VERSION 5.8 ;
BUSBITCHARS "[]" ;
DIVIDERCHAR "/" ;
UNITS
    DATABASE MICRONS 1000 ;
END UNITS

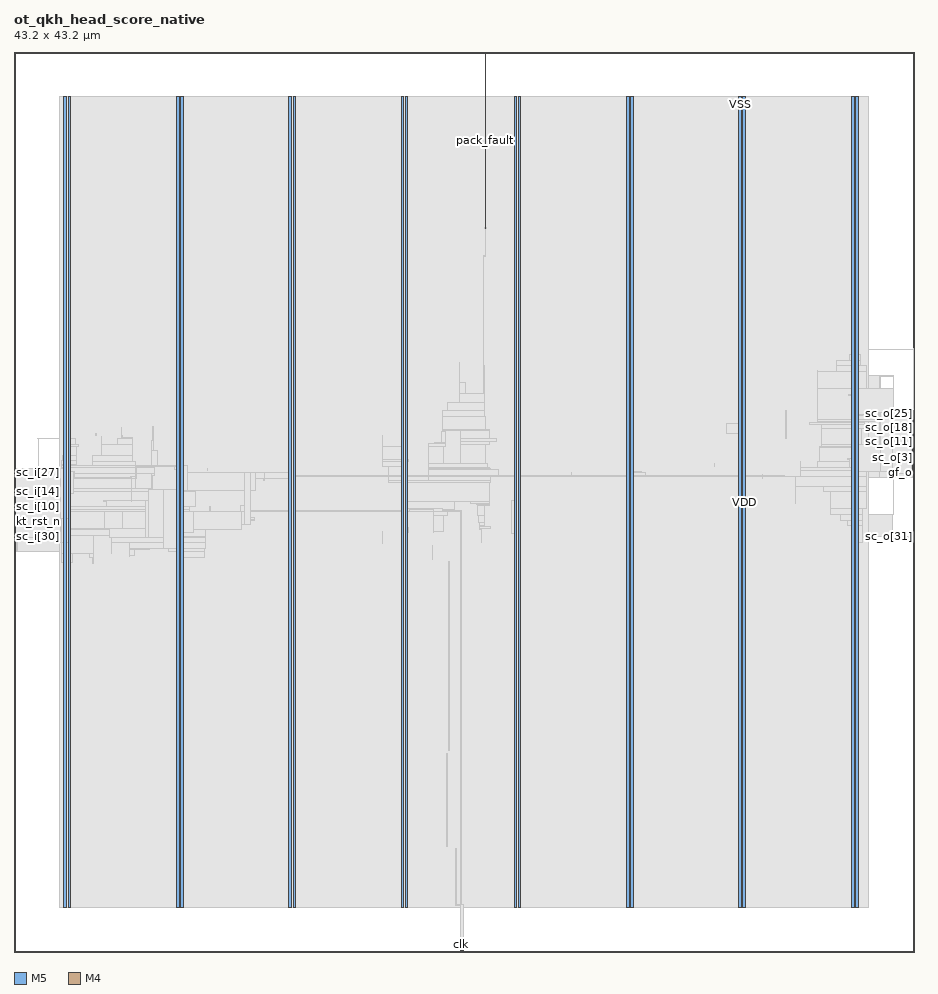
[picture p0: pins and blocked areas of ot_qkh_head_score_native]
MACRO ot_qkh_head_score_native
  FOREIGN ot_qkh_head_score_native 0 0 ;
  CLASS BLOCK ;
  SIZE 43.2 BY 43.2 ;
  PIN clk
    DIRECTION INPUT ;
    USE SIGNAL ;
    PORT
      LAYER M5 ;
        RECT  21.456 0 21.48 0.084 ;
    END
  END clk
  PIN gf_i
    DIRECTION INPUT ;
    USE SIGNAL ;
    PORT
      LAYER M4 ;
        RECT  0 20.208 0.084 20.232 ;
    END
  END gf_i
  PIN gf_o
    DIRECTION OUTPUT ;
    USE SIGNAL ;
    PORT
      LAYER M4 ;
        RECT  43.116 22.992 43.2 23.016 ;
    END
  END gf_o
  PIN kt_rst_n
    DIRECTION OUTPUT ;
    USE SIGNAL ;
    PORT
      LAYER M4 ;
        RECT  0 20.304 0.084 20.328 ;
    END
  END kt_rst_n
  PIN pack_fault
    DIRECTION INPUT ;
    USE SIGNAL ;
    PORT
      LAYER M5 ;
        RECT  22.608 43.116 22.632 43.2 ;
    END
    PORT
      LAYER M5 ;
        RECT  22.608 34.741 22.632 43.152 ;
    END
  END pack_fault
  PIN rst_n
    DIRECTION INPUT ;
    USE SIGNAL ;
    PORT
      LAYER M5 ;
        RECT  21.552 0 21.576 0.084 ;
    END
  END rst_n
  PIN sc_i[0]
    DIRECTION INPUT ;
    USE SIGNAL ;
    PORT
      LAYER M4 ;
        RECT  0 20.4 0.084 20.424 ;
    END
  END sc_i[0]
  PIN sc_i[10]
    DIRECTION INPUT ;
    USE SIGNAL ;
    PORT
      LAYER M4 ;
        RECT  0 21.36 0.084 21.384 ;
    END
  END sc_i[10]
  PIN sc_i[11]
    DIRECTION INPUT ;
    USE SIGNAL ;
    PORT
      LAYER M4 ;
        RECT  0 21.456 0.084 21.48 ;
    END
  END sc_i[11]
  PIN sc_i[12]
    DIRECTION INPUT ;
    USE SIGNAL ;
    PORT
      LAYER M4 ;
        RECT  0 21.552 0.084 21.576 ;
    END
  END sc_i[12]
  PIN sc_i[13]
    DIRECTION INPUT ;
    USE SIGNAL ;
    PORT
      LAYER M4 ;
        RECT  0 21.648 0.084 21.672 ;
    END
  END sc_i[13]
  PIN sc_i[14]
    DIRECTION INPUT ;
    USE SIGNAL ;
    PORT
      LAYER M4 ;
        RECT  0 21.744 0.084 21.768 ;
    END
  END sc_i[14]
  PIN sc_i[15]
    DIRECTION INPUT ;
    USE SIGNAL ;
    PORT
      LAYER M4 ;
        RECT  0 21.84 0.084 21.864 ;
    END
  END sc_i[15]
  PIN sc_i[16]
    DIRECTION INPUT ;
    USE SIGNAL ;
    PORT
      LAYER M4 ;
        RECT  0 21.936 0.084 21.96 ;
    END
  END sc_i[16]
  PIN sc_i[17]
    DIRECTION INPUT ;
    USE SIGNAL ;
    PORT
      LAYER M4 ;
        RECT  0 22.032 0.084 22.056 ;
    END
  END sc_i[17]
  PIN sc_i[18]
    DIRECTION INPUT ;
    USE SIGNAL ;
    PORT
      LAYER M4 ;
        RECT  0 22.128 0.084 22.152 ;
    END
  END sc_i[18]
  PIN sc_i[19]
    DIRECTION INPUT ;
    USE SIGNAL ;
    PORT
      LAYER M4 ;
        RECT  0 22.224 0.084 22.248 ;
    END
  END sc_i[19]
  PIN sc_i[1]
    DIRECTION INPUT ;
    USE SIGNAL ;
    PORT
      LAYER M4 ;
        RECT  0 20.496 0.084 20.52 ;
    END
  END sc_i[1]
  PIN sc_i[20]
    DIRECTION INPUT ;
    USE SIGNAL ;
    PORT
      LAYER M4 ;
        RECT  0 22.32 0.084 22.344 ;
    END
  END sc_i[20]
  PIN sc_i[21]
    DIRECTION INPUT ;
    USE SIGNAL ;
    PORT
      LAYER M4 ;
        RECT  0 22.416 0.084 22.44 ;
    END
  END sc_i[21]
  PIN sc_i[22]
    DIRECTION INPUT ;
    USE SIGNAL ;
    PORT
      LAYER M4 ;
        RECT  0 22.512 0.084 22.536 ;
    END
  END sc_i[22]
  PIN sc_i[23]
    DIRECTION INPUT ;
    USE SIGNAL ;
    PORT
      LAYER M4 ;
        RECT  0 22.608 0.084 22.632 ;
    END
  END sc_i[23]
  PIN sc_i[24]
    DIRECTION INPUT ;
    USE SIGNAL ;
    PORT
      LAYER M4 ;
        RECT  0 22.704 0.084 22.728 ;
    END
  END sc_i[24]
  PIN sc_i[25]
    DIRECTION INPUT ;
    USE SIGNAL ;
    PORT
      LAYER M4 ;
        RECT  0 22.8 0.084 22.824 ;
    END
  END sc_i[25]
  PIN sc_i[26]
    DIRECTION INPUT ;
    USE SIGNAL ;
    PORT
      LAYER M4 ;
        RECT  0 22.896 0.084 22.92 ;
    END
  END sc_i[26]
  PIN sc_i[27]
    DIRECTION INPUT ;
    USE SIGNAL ;
    PORT
      LAYER M4 ;
        RECT  0 22.992 0.084 23.016 ;
    END
  END sc_i[27]
  PIN sc_i[28]
    DIRECTION INPUT ;
    USE SIGNAL ;
    PORT
      LAYER M4 ;
        RECT  0 23.088 0.084 23.112 ;
    END
  END sc_i[28]
  PIN sc_i[29]
    DIRECTION INPUT ;
    USE SIGNAL ;
    PORT
      LAYER M4 ;
        RECT  0 23.184 0.084 23.208 ;
    END
  END sc_i[29]
  PIN sc_i[2]
    DIRECTION INPUT ;
    USE SIGNAL ;
    PORT
      LAYER M4 ;
        RECT  0 20.592 0.084 20.616 ;
    END
  END sc_i[2]
  PIN sc_i[30]
    DIRECTION INPUT ;
    USE SIGNAL ;
    PORT
      LAYER M4 ;
        RECT  0 19.92 0.084 19.944 ;
    END
  END sc_i[30]
  PIN sc_i[31]
    DIRECTION INPUT ;
    USE SIGNAL ;
    PORT
      LAYER M4 ;
        RECT  0 20.016 0.084 20.04 ;
    END
  END sc_i[31]
  PIN sc_i[3]
    DIRECTION INPUT ;
    USE SIGNAL ;
    PORT
      LAYER M4 ;
        RECT  0 20.688 0.084 20.712 ;
    END
  END sc_i[3]
  PIN sc_i[4]
    DIRECTION INPUT ;
    USE SIGNAL ;
    PORT
      LAYER M4 ;
        RECT  0 20.784 0.084 20.808 ;
    END
  END sc_i[4]
  PIN sc_i[5]
    DIRECTION INPUT ;
    USE SIGNAL ;
    PORT
      LAYER M4 ;
        RECT  0 20.88 0.084 20.904 ;
    END
  END sc_i[5]
  PIN sc_i[6]
    DIRECTION INPUT ;
    USE SIGNAL ;
    PORT
      LAYER M4 ;
        RECT  0 20.976 0.084 21 ;
    END
  END sc_i[6]
  PIN sc_i[7]
    DIRECTION INPUT ;
    USE SIGNAL ;
    PORT
      LAYER M4 ;
        RECT  0 21.072 0.084 21.096 ;
    END
  END sc_i[7]
  PIN sc_i[8]
    DIRECTION INPUT ;
    USE SIGNAL ;
    PORT
      LAYER M4 ;
        RECT  0 21.168 0.084 21.192 ;
    END
  END sc_i[8]
  PIN sc_i[9]
    DIRECTION INPUT ;
    USE SIGNAL ;
    PORT
      LAYER M4 ;
        RECT  0 21.264 0.084 21.288 ;
    END
  END sc_i[9]
  PIN sc_o[0]
    DIRECTION OUTPUT ;
    USE SIGNAL ;
    PORT
      LAYER M4 ;
        RECT  43.116 23.088 43.2 23.112 ;
    END
  END sc_o[0]
  PIN sc_o[10]
    DIRECTION OUTPUT ;
    USE SIGNAL ;
    PORT
      LAYER M4 ;
        RECT  43.116 24.048 43.2 24.072 ;
    END
  END sc_o[10]
  PIN sc_o[11]
    DIRECTION OUTPUT ;
    USE SIGNAL ;
    PORT
      LAYER M4 ;
        RECT  43.116 24.144 43.2 24.168 ;
    END
  END sc_o[11]
  PIN sc_o[12]
    DIRECTION OUTPUT ;
    USE SIGNAL ;
    PORT
      LAYER M4 ;
        RECT  43.116 24.24 43.2 24.264 ;
    END
  END sc_o[12]
  PIN sc_o[13]
    DIRECTION OUTPUT ;
    USE SIGNAL ;
    PORT
      LAYER M4 ;
        RECT  43.116 24.336 43.2 24.36 ;
    END
  END sc_o[13]
  PIN sc_o[14]
    DIRECTION OUTPUT ;
    USE SIGNAL ;
    PORT
      LAYER M4 ;
        RECT  43.116 24.432 43.2 24.456 ;
    END
  END sc_o[14]
  PIN sc_o[15]
    DIRECTION OUTPUT ;
    USE SIGNAL ;
    PORT
      LAYER M4 ;
        RECT  43.116 24.528 43.2 24.552 ;
    END
  END sc_o[15]
  PIN sc_o[16]
    DIRECTION OUTPUT ;
    USE SIGNAL ;
    PORT
      LAYER M4 ;
        RECT  43.116 24.624 43.2 24.648 ;
    END
  END sc_o[16]
  PIN sc_o[17]
    DIRECTION OUTPUT ;
    USE SIGNAL ;
    PORT
      LAYER M4 ;
        RECT  43.116 24.72 43.2 24.744 ;
    END
  END sc_o[17]
  PIN sc_o[18]
    DIRECTION OUTPUT ;
    USE SIGNAL ;
    PORT
      LAYER M4 ;
        RECT  43.116 24.816 43.2 24.84 ;
    END
  END sc_o[18]
  PIN sc_o[19]
    DIRECTION OUTPUT ;
    USE SIGNAL ;
    PORT
      LAYER M4 ;
        RECT  43.116 24.912 43.2 24.936 ;
    END
  END sc_o[19]
  PIN sc_o[1]
    DIRECTION OUTPUT ;
    USE SIGNAL ;
    PORT
      LAYER M4 ;
        RECT  43.116 23.184 43.2 23.208 ;
    END
  END sc_o[1]
  PIN sc_o[20]
    DIRECTION OUTPUT ;
    USE SIGNAL ;
    PORT
      LAYER M4 ;
        RECT  43.116 25.008 43.2 25.032 ;
    END
  END sc_o[20]
  PIN sc_o[21]
    DIRECTION OUTPUT ;
    USE SIGNAL ;
    PORT
      LAYER M4 ;
        RECT  43.116 25.104 43.2 25.128 ;
    END
  END sc_o[21]
  PIN sc_o[22]
    DIRECTION OUTPUT ;
    USE SIGNAL ;
    PORT
      LAYER M4 ;
        RECT  43.116 25.2 43.2 25.224 ;
    END
  END sc_o[22]
  PIN sc_o[23]
    DIRECTION OUTPUT ;
    USE SIGNAL ;
    PORT
      LAYER M4 ;
        RECT  43.116 25.296 43.2 25.32 ;
    END
  END sc_o[23]
  PIN sc_o[24]
    DIRECTION OUTPUT ;
    USE SIGNAL ;
    PORT
      LAYER M4 ;
        RECT  43.116 25.392 43.2 25.416 ;
    END
  END sc_o[24]
  PIN sc_o[25]
    DIRECTION OUTPUT ;
    USE SIGNAL ;
    PORT
      LAYER M4 ;
        RECT  43.116 25.488 43.2 25.512 ;
    END
  END sc_o[25]
  PIN sc_o[26]
    DIRECTION OUTPUT ;
    USE SIGNAL ;
    PORT
      LAYER M4 ;
        RECT  43.116 25.584 43.2 25.608 ;
    END
  END sc_o[26]
  PIN sc_o[27]
    DIRECTION OUTPUT ;
    USE SIGNAL ;
    PORT
      LAYER M4 ;
        RECT  43.116 25.68 43.2 25.704 ;
    END
  END sc_o[27]
  PIN sc_o[28]
    DIRECTION OUTPUT ;
    USE SIGNAL ;
    PORT
      LAYER M4 ;
        RECT  43.116 25.776 43.2 25.8 ;
    END
  END sc_o[28]
  PIN sc_o[29]
    DIRECTION OUTPUT ;
    USE SIGNAL ;
    PORT
      LAYER M4 ;
        RECT  43.116 25.872 43.2 25.896 ;
    END
  END sc_o[29]
  PIN sc_o[2]
    DIRECTION OUTPUT ;
    USE SIGNAL ;
    PORT
      LAYER M4 ;
        RECT  43.116 23.28 43.2 23.304 ;
    END
  END sc_o[2]
  PIN sc_o[30]
    DIRECTION OUTPUT ;
    USE SIGNAL ;
    PORT
      LAYER M4 ;
        RECT  43.116 25.968 43.2 25.992 ;
    END
  END sc_o[30]
  PIN sc_o[31]
    DIRECTION OUTPUT ;
    USE SIGNAL ;
    PORT
      LAYER M4 ;
        RECT  43.116 19.92 43.2 19.944 ;
    END
  END sc_o[31]
  PIN sc_o[3]
    DIRECTION OUTPUT ;
    USE SIGNAL ;
    PORT
      LAYER M4 ;
        RECT  43.116 23.376 43.2 23.4 ;
    END
  END sc_o[3]
  PIN sc_o[4]
    DIRECTION OUTPUT ;
    USE SIGNAL ;
    PORT
      LAYER M4 ;
        RECT  43.116 23.472 43.2 23.496 ;
    END
  END sc_o[4]
  PIN sc_o[5]
    DIRECTION OUTPUT ;
    USE SIGNAL ;
    PORT
      LAYER M4 ;
        RECT  43.116 23.568 43.2 23.592 ;
    END
  END sc_o[5]
  PIN sc_o[6]
    DIRECTION OUTPUT ;
    USE SIGNAL ;
    PORT
      LAYER M4 ;
        RECT  43.116 23.664 43.2 23.688 ;
    END
  END sc_o[6]
  PIN sc_o[7]
    DIRECTION OUTPUT ;
    USE SIGNAL ;
    PORT
      LAYER M4 ;
        RECT  43.116 23.76 43.2 23.784 ;
    END
  END sc_o[7]
  PIN sc_o[8]
    DIRECTION OUTPUT ;
    USE SIGNAL ;
    PORT
      LAYER M4 ;
        RECT  43.116 23.856 43.2 23.88 ;
    END
  END sc_o[8]
  PIN sc_o[9]
    DIRECTION OUTPUT ;
    USE SIGNAL ;
    PORT
      LAYER M4 ;
        RECT  43.116 23.952 43.2 23.976 ;
    END
  END sc_o[9]
  PIN sf_i
    DIRECTION INPUT ;
    USE SIGNAL ;
    PORT
      LAYER M4 ;
        RECT  0 20.112 0.084 20.136 ;
    END
  END sf_i
  PIN sf_o
    DIRECTION OUTPUT ;
    USE SIGNAL ;
    PORT
      LAYER M4 ;
        RECT  43.116 20.016 43.2 20.04 ;
    END
  END sf_o
  PIN VDD
    DIRECTION INOUT ;
    USE POWER ;
    PORT
      LAYER M5 ;
        RECT  40.392 2.151 40.512 41.049 ;
        RECT  34.992 2.151 35.112 41.049 ;
        RECT  29.592 2.151 29.712 41.049 ;
        RECT  24.192 2.151 24.312 41.049 ;
        RECT  18.792 2.151 18.912 41.049 ;
        RECT  13.392 2.151 13.512 41.049 ;
        RECT  7.992 2.151 8.112 41.049 ;
        RECT  2.592 2.151 2.712 41.049 ;
    END
  END VDD
  PIN VSS
    DIRECTION INOUT ;
    USE GROUND ;
    PORT
      LAYER M5 ;
        RECT  40.2 2.137 40.32 41.063 ;
        RECT  34.8 2.137 34.92 41.063 ;
        RECT  29.4 2.137 29.52 41.063 ;
        RECT  24 2.137 24.12 41.063 ;
        RECT  18.6 2.137 18.72 41.063 ;
        RECT  13.2 2.137 13.32 41.063 ;
        RECT  7.8 2.137 7.92 41.063 ;
        RECT  2.4 2.137 2.52 41.063 ;
    END
  END VSS
  # OT_OBS_CLOSED layer=M5 d_um=1.536 added=1
  OBS
    LAYER RVTN ;
     RECT  2.16 2.16 41.04 2.295 ;
     RECT  2.16 2.565 41.04 2.835 ;
     RECT  2.16 3.105 41.04 3.375 ;
     RECT  2.16 3.645 41.04 3.915 ;
     RECT  2.16 4.185 41.04 4.455 ;
     RECT  2.16 4.725 41.04 4.995 ;
     RECT  2.16 5.265 41.04 5.535 ;
     RECT  2.16 5.805 41.04 6.075 ;
     RECT  2.16 6.345 41.04 6.615 ;
     RECT  2.16 6.885 41.04 7.155 ;
     RECT  2.16 7.425 41.04 7.695 ;
     RECT  2.16 7.965 41.04 8.235 ;
     RECT  2.16 8.505 41.04 8.775 ;
     RECT  2.16 9.045 41.04 9.315 ;
     RECT  2.16 9.585 41.04 9.855 ;
     RECT  2.16 10.125 41.04 10.395 ;
     RECT  2.16 10.665 41.04 10.935 ;
     RECT  2.16 11.205 41.04 11.475 ;
     RECT  2.16 11.745 41.04 12.015 ;
     RECT  2.16 12.285 41.04 12.555 ;
     RECT  2.16 12.825 41.04 13.095 ;
     RECT  2.16 13.365 41.04 13.635 ;
     RECT  2.16 13.905 41.04 14.175 ;
     RECT  2.16 14.445 41.04 14.715 ;
     RECT  2.16 14.985 41.04 15.255 ;
     RECT  2.16 15.525 41.04 15.795 ;
     RECT  2.16 16.065 41.04 16.335 ;
     RECT  2.16 16.605 41.04 16.875 ;
     RECT  2.16 17.145 41.04 17.415 ;
     RECT  2.16 17.685 41.04 17.955 ;
     RECT  2.16 18.225 41.04 18.495 ;
     RECT  2.16 18.765 41.04 19.035 ;
     RECT  2.16 19.305 41.04 19.575 ;
     RECT  2.16 19.845 41.04 20.115 ;
     RECT  2.16 20.385 41.04 20.655 ;
     RECT  2.16 20.925 41.04 21.195 ;
     RECT  2.16 21.465 41.04 21.735 ;
     RECT  2.16 22.005 41.04 22.275 ;
     RECT  2.16 22.545 41.04 22.815 ;
     RECT  2.16 23.085 41.04 23.355 ;
     RECT  2.16 23.625 41.04 23.895 ;
     RECT  2.16 24.165 41.04 24.435 ;
     RECT  2.16 24.705 41.04 24.975 ;
     RECT  2.16 25.245 41.04 25.515 ;
     RECT  2.16 25.785 41.04 26.055 ;
     RECT  2.16 26.325 41.04 26.595 ;
     RECT  2.16 26.865 41.04 27.135 ;
     RECT  2.16 27.405 41.04 27.675 ;
     RECT  2.16 27.945 41.04 28.215 ;
     RECT  2.16 28.485 41.04 28.755 ;
     RECT  2.16 29.025 41.04 29.295 ;
     RECT  2.16 29.565 41.04 29.835 ;
     RECT  2.16 30.105 41.04 30.375 ;
     RECT  2.16 30.645 41.04 30.915 ;
     RECT  2.16 31.185 41.04 31.455 ;
     RECT  2.16 31.725 41.04 31.995 ;
     RECT  2.16 32.265 41.04 32.535 ;
     RECT  2.16 32.805 41.04 33.075 ;
     RECT  2.16 33.345 41.04 33.615 ;
     RECT  2.16 33.885 41.04 34.155 ;
     RECT  2.16 34.425 41.04 34.695 ;
     RECT  2.16 34.965 41.04 35.235 ;
     RECT  2.16 35.505 41.04 35.775 ;
     RECT  2.16 36.045 41.04 36.315 ;
     RECT  2.16 36.585 41.04 36.855 ;
     RECT  2.16 37.125 41.04 37.395 ;
     RECT  2.16 37.665 41.04 37.935 ;
     RECT  2.16 38.205 41.04 38.475 ;
     RECT  2.16 38.745 41.04 39.015 ;
     RECT  2.16 39.285 41.04 39.555 ;
     RECT  2.16 39.825 41.04 40.095 ;
     RECT  2.16 40.365 41.04 40.635 ;
     RECT  2.16 40.905 41.04 41.04 ;
    LAYER RVTP ;
     RECT  2.16 2.295 41.04 2.565 ;
     RECT  2.16 2.835 41.04 3.105 ;
     RECT  2.16 3.375 41.04 3.645 ;
     RECT  2.16 3.915 41.04 4.185 ;
     RECT  2.16 4.455 41.04 4.725 ;
     RECT  2.16 4.995 41.04 5.265 ;
     RECT  2.16 5.535 41.04 5.805 ;
     RECT  2.16 6.075 41.04 6.345 ;
     RECT  2.16 6.615 41.04 6.885 ;
     RECT  2.16 7.155 41.04 7.425 ;
     RECT  2.16 7.695 41.04 7.965 ;
     RECT  2.16 8.235 41.04 8.505 ;
     RECT  2.16 8.775 41.04 9.045 ;
     RECT  2.16 9.315 41.04 9.585 ;
     RECT  2.16 9.855 41.04 10.125 ;
     RECT  2.16 10.395 41.04 10.665 ;
     RECT  2.16 10.935 41.04 11.205 ;
     RECT  2.16 11.475 41.04 11.745 ;
     RECT  2.16 12.015 41.04 12.285 ;
     RECT  2.16 12.555 41.04 12.825 ;
     RECT  2.16 13.095 41.04 13.365 ;
     RECT  2.16 13.635 41.04 13.905 ;
     RECT  2.16 14.175 41.04 14.445 ;
     RECT  2.16 14.715 41.04 14.985 ;
     RECT  2.16 15.255 41.04 15.525 ;
     RECT  2.16 15.795 41.04 16.065 ;
     RECT  2.16 16.335 41.04 16.605 ;
     RECT  2.16 16.875 41.04 17.145 ;
     RECT  2.16 17.415 41.04 17.685 ;
     RECT  2.16 17.955 41.04 18.225 ;
     RECT  2.16 18.495 41.04 18.765 ;
     RECT  2.16 19.035 41.04 19.305 ;
     RECT  2.16 19.575 41.04 19.845 ;
     RECT  2.16 20.115 41.04 20.385 ;
     RECT  2.16 20.655 41.04 20.925 ;
     RECT  2.16 21.195 41.04 21.465 ;
     RECT  2.16 21.735 41.04 22.005 ;
     RECT  2.16 22.275 41.04 22.545 ;
     RECT  2.16 22.815 41.04 23.085 ;
     RECT  2.16 23.355 41.04 23.625 ;
     RECT  2.16 23.895 41.04 24.165 ;
     RECT  2.16 24.435 41.04 24.705 ;
     RECT  2.16 24.975 41.04 25.245 ;
     RECT  2.16 25.515 41.04 25.785 ;
     RECT  2.16 26.055 41.04 26.325 ;
     RECT  2.16 26.595 41.04 26.865 ;
     RECT  2.16 27.135 41.04 27.405 ;
     RECT  2.16 27.675 41.04 27.945 ;
     RECT  2.16 28.215 41.04 28.485 ;
     RECT  2.16 28.755 41.04 29.025 ;
     RECT  2.16 29.295 41.04 29.565 ;
     RECT  2.16 29.835 41.04 30.105 ;
     RECT  2.16 30.375 41.04 30.645 ;
     RECT  2.16 30.915 41.04 31.185 ;
     RECT  2.16 31.455 41.04 31.725 ;
     RECT  2.16 31.995 41.04 32.265 ;
     RECT  2.16 32.535 41.04 32.805 ;
     RECT  2.16 33.075 41.04 33.345 ;
     RECT  2.16 33.615 41.04 33.885 ;
     RECT  2.16 34.155 41.04 34.425 ;
     RECT  2.16 34.695 41.04 34.965 ;
     RECT  2.16 35.235 41.04 35.505 ;
     RECT  2.16 35.775 41.04 36.045 ;
     RECT  2.16 36.315 41.04 36.585 ;
     RECT  2.16 36.855 41.04 37.125 ;
     RECT  2.16 37.395 41.04 37.665 ;
     RECT  2.16 37.935 41.04 38.205 ;
     RECT  2.16 38.475 41.04 38.745 ;
     RECT  2.16 39.015 41.04 39.285 ;
     RECT  2.16 39.555 41.04 39.825 ;
     RECT  2.16 40.095 41.04 40.365 ;
     RECT  2.16 40.635 41.04 40.905 ;
    LAYER M1 ;
     RECT  2.16 2.151 41.04 41.049 ;
    LAYER M2 ;
     RECT  0.103 19.656 0.139 19.674 ;
     RECT  0.139 19.242 0.175 19.674 ;
     RECT  0.175 19.242 2.16 19.908 ;
     RECT  0.175 20.7 2.16 20.718 ;
     RECT  0.535 22.014 2.16 22.032 ;
     RECT  1.147 24.642 2.16 24.66 ;
     RECT  2.16 2.151 41.04 41.049 ;
     RECT  41.04 22.788 41.567 27.666 ;
     RECT  41.567 26.568 41.603 27.666 ;
     RECT  41.603 26.568 41.891 26.586 ;
     RECT  41.04 19.926 42.179 21.024 ;
     RECT  41.567 22.788 42.179 25.704 ;
     RECT  42.179 21.006 42.215 21.024 ;
     RECT  41.603 27.648 42.215 27.666 ;
     RECT  42.179 19.926 43.115 19.944 ;
     RECT  42.179 22.788 43.115 23.922 ;
     RECT  41.04 28.926 43.187 28.944 ;
    LAYER M3 ;
     RECT  2.415 2.143 2.505 2.413 ;
     RECT  7.815 2.143 7.905 2.413 ;
     RECT  13.215 2.143 13.305 2.413 ;
     RECT  18.615 2.143 18.705 2.413 ;
     RECT  24.015 2.143 24.105 2.413 ;
     RECT  29.415 2.143 29.505 2.413 ;
     RECT  34.815 2.143 34.905 2.413 ;
     RECT  40.215 2.143 40.305 2.413 ;
     RECT  21.204 2.251 21.222 4.955 ;
     RECT  20.772 5.071 20.79 9.545 ;
     RECT  2.415 2.413 2.697 18.697 ;
     RECT  20.88 9.661 20.898 18.725 ;
     RECT  3.78 18.661 3.798 18.931 ;
     RECT  7.815 2.413 8.097 18.931 ;
     RECT  5.544 19.003 5.562 19.039 ;
     RECT  2.304 18.697 2.826 19.111 ;
     RECT  3.6 18.931 3.798 19.111 ;
     RECT  7.815 18.931 9.126 19.237 ;
     RECT  5.544 19.039 5.778 19.309 ;
     RECT  7.416 19.237 9.126 19.381 ;
     RECT  5.544 19.309 6.498 19.387 ;
     RECT  7.416 19.381 9.198 19.387 ;
     RECT  20.088 18.841 20.106 19.535 ;
     RECT  40.215 2.413 40.497 19.615 ;
     RECT  0.144 19.237 0.162 19.651 ;
     RECT  4.68 19.111 4.698 19.651 ;
     RECT  5.544 19.387 9.198 19.651 ;
     RECT  40.176 19.615 40.497 19.651 ;
     RECT  0.108 19.651 0.162 19.885 ;
     RECT  4.68 19.651 9.198 19.898 ;
     RECT  4.572 19.898 9.198 19.949 ;
     RECT  2.304 19.111 3.798 20.011 ;
     RECT  4.572 19.949 6.498 20.011 ;
     RECT  43.092 19.921 43.11 20.045 ;
     RECT  24.015 2.413 24.297 20.083 ;
     RECT  18.615 2.413 18.897 20.155 ;
     RECT  17.676 19.615 17.694 20.183 ;
     RECT  20.124 20.119 20.142 20.191 ;
     RECT  0.108 19.885 0.198 20.203 ;
     RECT  22.428 19.651 22.446 20.281 ;
     RECT  2.304 20.011 6.498 20.309 ;
     RECT  22.356 20.281 22.446 20.317 ;
     RECT  0.108 20.203 0.342 20.333 ;
     RECT  2.304 20.309 6.426 20.345 ;
     RECT  7.236 19.949 9.198 20.345 ;
     RECT  18.615 20.155 18.954 20.381 ;
     RECT  7.344 20.345 9.198 20.389 ;
     RECT  22.356 20.317 22.878 20.417 ;
     RECT  22.356 20.417 22.59 20.461 ;
     RECT  40.176 19.651 40.734 20.461 ;
     RECT  10.872 20.299 10.89 20.539 ;
     RECT  7.344 20.389 9.63 20.579 ;
     RECT  42.156 19.915 42.174 20.579 ;
     RECT  7.344 20.579 9.558 20.615 ;
     RECT  10.872 20.539 11.322 20.623 ;
     RECT  22.32 20.461 22.59 20.623 ;
     RECT  7.344 20.615 8.622 20.651 ;
     RECT  39.996 20.461 40.734 20.695 ;
     RECT  10.8 20.623 11.322 20.731 ;
     RECT  10.8 20.731 11.538 20.759 ;
     RECT  10.872 20.759 11.538 20.849 ;
     RECT  22.284 20.623 22.59 20.929 ;
     RECT  20.124 20.191 20.61 20.965 ;
     RECT  39.672 20.695 40.734 21.001 ;
     RECT  2.304 20.345 4.338 21.163 ;
     RECT  5.22 20.345 6.426 21.163 ;
     RECT  18.615 20.381 18.897 21.163 ;
     RECT  20.124 20.965 20.826 21.163 ;
     RECT  2.304 21.163 6.426 21.235 ;
     RECT  7.344 20.651 8.442 21.235 ;
     RECT  18.615 21.163 20.826 21.235 ;
     RECT  39.204 21.001 40.734 21.271 ;
     RECT  9.396 20.615 9.414 21.389 ;
     RECT  2.304 21.235 8.442 21.397 ;
     RECT  10.872 20.849 11.358 21.425 ;
     RECT  22.248 20.929 22.59 21.433 ;
     RECT  11.052 21.425 11.358 21.461 ;
     RECT  22.248 21.433 22.842 21.469 ;
     RECT  34.815 2.413 35.097 21.505 ;
     RECT  22.212 21.469 22.842 21.541 ;
     RECT  18.615 21.235 21.15 21.631 ;
     RECT  21.924 21.541 22.842 21.631 ;
     RECT  0.18 20.333 0.198 21.643 ;
     RECT  23.868 20.083 24.297 21.659 ;
     RECT  34.776 21.505 35.097 21.659 ;
     RECT  0.18 21.643 0.342 21.739 ;
     RECT  0.144 21.739 0.342 22.009 ;
     RECT  39.204 21.271 40.914 22.081 ;
     RECT  2.304 21.397 8.694 22.109 ;
     RECT  2.304 22.109 6.642 22.123 ;
     RECT  11.16 21.461 11.358 22.165 ;
     RECT  7.416 22.109 8.694 22.199 ;
     RECT  7.56 22.199 8.694 22.222 ;
     RECT  2.268 22.123 6.642 22.235 ;
     RECT  11.16 22.165 11.574 22.235 ;
     RECT  0.144 22.009 0.558 22.253 ;
     RECT  7.815 22.222 8.694 22.315 ;
     RECT  37.512 21.541 37.53 22.351 ;
     RECT  38.844 22.081 40.914 22.351 ;
     RECT  7.815 22.315 9.054 22.469 ;
     RECT  11.376 22.235 11.574 22.469 ;
     RECT  11.448 22.469 11.574 22.505 ;
     RECT  18.615 21.631 22.842 22.549 ;
     RECT  9.072 22.549 9.09 22.649 ;
     RECT  17.964 22.549 22.878 22.649 ;
     RECT  11.988 22.621 12.006 22.781 ;
     RECT  37.512 22.351 40.914 22.843 ;
     RECT  36.972 22.843 40.914 22.847 ;
     RECT  36.972 22.847 36.99 22.883 ;
     RECT  6.624 22.235 6.642 22.891 ;
     RECT  19.908 22.649 22.878 22.891 ;
     RECT  29.415 2.413 29.697 22.891 ;
     RECT  35.928 22.711 35.946 22.919 ;
     RECT  2.268 22.235 5.85 22.981 ;
     RECT  6.624 22.891 6.75 22.981 ;
     RECT  26.748 22.891 26.766 23.009 ;
     RECT  29.415 22.891 30.33 23.009 ;
     RECT  42.192 21.001 42.21 23.021 ;
     RECT  29.415 23.009 30.114 23.045 ;
     RECT  0.144 22.253 0.162 23.069 ;
     RECT  7.815 22.469 8.334 23.089 ;
     RECT  37.728 22.847 40.914 23.117 ;
     RECT  19.908 22.891 23.274 23.153 ;
     RECT  7.776 23.089 8.334 23.161 ;
     RECT  43.092 22.783 43.11 23.161 ;
     RECT  9.288 23.089 9.306 23.189 ;
     RECT  19.908 23.153 22.878 23.189 ;
     RECT  43.056 23.161 43.11 23.251 ;
     RECT  2.268 22.981 6.75 23.279 ;
     RECT  19.908 23.189 22.842 23.279 ;
     RECT  37.728 23.117 40.806 23.279 ;
     RECT  17.964 22.649 18.897 23.287 ;
     RECT  6.624 23.279 6.75 23.323 ;
     RECT  2.268 23.279 5.85 23.351 ;
     RECT  7.704 23.161 8.334 23.351 ;
     RECT  7.815 23.351 8.334 23.357 ;
     RECT  2.268 23.351 3.006 23.387 ;
     RECT  19.908 23.279 22.734 23.459 ;
     RECT  33.624 23.323 33.642 23.459 ;
     RECT  17.676 23.287 18.897 23.521 ;
     RECT  3.78 23.351 5.85 23.549 ;
     RECT  37.728 23.279 37.746 23.549 ;
     RECT  38.592 23.279 40.806 23.549 ;
     RECT  34.815 21.659 35.097 23.557 ;
     RECT  2.304 23.387 3.006 23.585 ;
     RECT  17.676 23.521 18.954 23.621 ;
     RECT  42.156 23.701 42.174 23.789 ;
     RECT  3.78 23.549 5.706 23.819 ;
     RECT  34.776 23.557 35.097 23.819 ;
     RECT  2.34 23.585 3.006 23.855 ;
     RECT  43.02 23.251 43.11 23.885 ;
     RECT  43.092 23.885 43.11 23.981 ;
     RECT  6.624 23.323 6.894 24.089 ;
     RECT  41.58 24.043 41.634 24.139 ;
     RECT  38.664 23.549 40.806 24.205 ;
     RECT  41.544 24.139 41.634 24.205 ;
     RECT  2.376 23.855 3.006 24.241 ;
     RECT  19.908 23.459 20.61 24.241 ;
     RECT  17.676 23.621 18.897 24.269 ;
     RECT  38.664 24.205 41.634 24.269 ;
     RECT  2.376 24.241 3.114 24.359 ;
     RECT  4.176 23.819 5.706 24.359 ;
     RECT  38.772 24.269 41.634 24.365 ;
     RECT  21.456 23.459 22.626 24.367 ;
     RECT  19.908 24.241 20.718 24.431 ;
     RECT  41.544 24.365 41.634 24.431 ;
     RECT  20.196 24.431 20.718 24.467 ;
     RECT  21.456 24.367 22.842 24.511 ;
     RECT  41.58 24.431 41.634 24.523 ;
     RECT  6.624 24.089 6.678 24.539 ;
     RECT  2.376 24.359 2.97 24.629 ;
     RECT  4.968 24.359 5.706 24.629 ;
     RECT  21.456 24.511 23.166 24.629 ;
     RECT  1.152 22.507 1.17 24.665 ;
     RECT  5.148 24.629 5.706 24.701 ;
     RECT  4.176 24.359 4.194 24.737 ;
     RECT  17.676 24.269 17.694 24.773 ;
     RECT  5.148 24.701 5.202 24.809 ;
     RECT  3.924 24.781 3.942 24.899 ;
     RECT  34.815 23.819 35.097 24.907 ;
     RECT  2.376 24.629 2.697 24.935 ;
     RECT  20.52 24.467 20.718 24.971 ;
     RECT  20.556 24.971 20.718 25.007 ;
     RECT  20.592 25.007 20.718 25.051 ;
     RECT  21.456 24.629 22.842 25.051 ;
     RECT  20.592 25.051 22.842 25.079 ;
     RECT  38.772 24.365 40.662 25.141 ;
     RECT  5.148 24.809 5.166 25.169 ;
     RECT  6.66 24.539 6.678 25.205 ;
     RECT  38.772 25.141 40.842 25.321 ;
     RECT  34.2 24.907 35.097 25.349 ;
     RECT  38.196 25.321 40.842 25.439 ;
     RECT  38.556 25.439 40.842 25.483 ;
     RECT  41.58 24.523 42.174 25.483 ;
     RECT  38.556 25.483 42.174 25.579 ;
     RECT  20.592 25.079 22.626 25.709 ;
     RECT  20.592 25.709 22.59 25.979 ;
     RECT  37.044 24.637 37.062 25.979 ;
     RECT  43.092 25.963 43.11 26.059 ;
     RECT  43.092 26.059 43.182 26.093 ;
     RECT  34.815 25.349 35.097 26.365 ;
     RECT  20.808 25.979 22.59 26.393 ;
     RECT  21.384 26.393 22.59 26.789 ;
     RECT  34.776 26.365 35.097 26.789 ;
     RECT  38.556 25.579 42.21 27.059 ;
     RECT  21.384 26.789 21.69 27.329 ;
     RECT  42.192 27.059 42.21 27.671 ;
     RECT  38.556 27.059 40.914 27.869 ;
     RECT  38.556 27.869 38.574 27.905 ;
     RECT  22.536 26.789 22.59 28.139 ;
     RECT  39.456 27.869 40.914 28.139 ;
     RECT  39.456 28.139 40.662 28.175 ;
     RECT  21.384 27.329 21.402 28.319 ;
     RECT  39.456 28.175 40.626 28.409 ;
     RECT  40.104 28.409 40.626 28.679 ;
     RECT  43.164 26.093 43.182 28.949 ;
     RECT  22.536 28.139 22.554 33.385 ;
     RECT  22.536 33.385 22.626 33.449 ;
     RECT  22.608 33.449 22.626 34.781 ;
     RECT  2.415 24.935 2.697 40.787 ;
     RECT  7.815 23.357 8.097 40.787 ;
     RECT  13.215 2.413 13.497 40.787 ;
     RECT  18.615 24.269 18.897 40.787 ;
     RECT  24.015 21.659 24.297 40.787 ;
     RECT  29.415 23.045 29.697 40.787 ;
     RECT  34.815 26.789 35.097 40.787 ;
     RECT  40.215 28.679 40.497 40.787 ;
     RECT  2.415 40.787 2.505 41.057 ;
     RECT  7.815 40.787 7.905 41.057 ;
     RECT  13.215 40.787 13.305 41.057 ;
     RECT  18.615 40.787 18.705 41.057 ;
     RECT  24.015 40.787 24.105 41.057 ;
     RECT  29.415 40.787 29.505 41.057 ;
     RECT  34.815 40.787 34.905 41.057 ;
     RECT  40.215 40.787 40.305 41.057 ;
    LAYER M4 ;
     RECT  0.06 19.92 2.252 23.208 ;
     RECT  2.252 19.68 2.408 23.208 ;
     RECT  2.408 2.148 2.512 41.052 ;
     RECT  2.512 2.418 2.704 40.782 ;
     RECT  2.704 20.304 2.729 23.064 ;
     RECT  2.729 22.032 2.873 23.064 ;
     RECT  2.873 22.752 2.909 23.064 ;
     RECT  4.273 21.648 4.417 21.672 ;
     RECT  2.729 20.304 4.561 20.328 ;
     RECT  2.909 22.752 5.605 22.776 ;
     RECT  5.605 22.752 5.821 22.824 ;
     RECT  5.821 22.752 5.861 23.352 ;
     RECT  4.561 19.92 6.289 20.328 ;
     RECT  4.417 21.408 6.289 21.672 ;
     RECT  6.289 19.92 6.433 21.672 ;
     RECT  6.433 19.92 7.153 22.2 ;
     RECT  7.153 19.392 7.808 22.2 ;
     RECT  5.861 23.328 7.808 23.352 ;
     RECT  7.808 2.148 7.912 41.052 ;
     RECT  7.912 2.418 8.104 40.782 ;
     RECT  8.104 22.176 8.345 23.352 ;
     RECT  8.104 20.16 8.597 21.144 ;
     RECT  8.597 20.304 10.901 21.144 ;
     RECT  10.901 20.544 11.077 21.144 ;
     RECT  8.345 22.176 11.077 23.016 ;
     RECT  11.077 20.544 11.333 23.016 ;
     RECT  11.333 21.168 11.369 23.016 ;
     RECT  11.369 22.176 11.585 23.016 ;
     RECT  11.585 22.752 12.035 23.016 ;
     RECT  12.035 22.752 12.061 22.872 ;
     RECT  11.369 21.168 13.208 21.192 ;
     RECT  12.061 22.848 13.208 22.872 ;
     RECT  13.208 2.148 13.312 41.052 ;
     RECT  13.312 2.418 13.504 40.782 ;
     RECT  13.504 21.168 18.608 21.192 ;
     RECT  13.504 22.848 18.608 22.872 ;
     RECT  18.608 2.148 18.712 41.052 ;
     RECT  18.712 2.418 18.904 40.782 ;
     RECT  18.904 21.168 19.001 21.288 ;
     RECT  19.001 21.264 20.113 21.288 ;
     RECT  20.113 21.168 20.549 21.288 ;
     RECT  20.549 21.168 21.491 21.192 ;
     RECT  21.193 2.256 21.587 2.28 ;
     RECT  22.597 34.752 22.681 34.776 ;
     RECT  18.904 22.848 24.008 22.872 ;
     RECT  24.008 2.148 24.112 41.052 ;
     RECT  24.112 2.418 24.304 40.782 ;
     RECT  24.304 22.848 29.408 22.872 ;
     RECT  29.408 2.148 29.512 41.052 ;
     RECT  29.512 2.418 29.704 40.782 ;
     RECT  29.704 22.848 34.808 22.872 ;
     RECT  34.808 2.148 34.912 41.052 ;
     RECT  34.912 2.418 35.104 40.782 ;
     RECT  35.104 22.848 37.001 22.872 ;
     RECT  39.985 23.664 40.093 23.688 ;
     RECT  40.093 23.28 40.208 23.688 ;
     RECT  40.057 26.736 40.208 26.76 ;
     RECT  40.208 2.148 40.312 41.052 ;
     RECT  40.312 2.418 40.504 40.782 ;
     RECT  40.504 25.776 41.497 25.8 ;
     RECT  41.497 25.776 41.533 25.896 ;
     RECT  40.504 23.088 41.569 24.36 ;
     RECT  41.533 25.488 41.569 25.896 ;
     RECT  41.569 23.088 42.181 25.896 ;
     RECT  42.145 19.92 43.081 19.944 ;
     RECT  42.181 22.992 43.081 25.896 ;
     RECT  43.081 19.92 43.164 20.04 ;
     RECT  43.081 22.992 43.164 26.088 ;
     RECT  43.164 26.064 43.193 26.088 ;
    LAYER M5 ;
     RECT  2.4 2.137 2.52 2.151 ;
     RECT  7.8 2.137 7.92 2.151 ;
     RECT  13.2 2.137 13.32 2.151 ;
     RECT  18.6 2.137 18.72 2.151 ;
     RECT  24 2.137 24.12 2.151 ;
     RECT  29.4 2.137 29.52 2.151 ;
     RECT  34.8 2.137 34.92 2.151 ;
     RECT  40.2 2.137 40.32 2.151 ;
     RECT  21.456 0.016 21.576 2.291 ;
     RECT  2.4 2.151 2.712 19.669 ;
     RECT  2.304 19.669 2.712 20.819 ;
     RECT  21.456 2.291 21.48 21.203 ;
     RECT  5.616 21.637 5.64 22.835 ;
     RECT  12 22.741 12.024 23.027 ;
     RECT  2.4 20.819 2.712 41.049 ;
     RECT  7.8 2.151 8.112 41.049 ;
     RECT  13.2 2.151 13.512 41.049 ;
     RECT  18.6 2.151 18.912 41.049 ;
     RECT  24 2.151 24.312 41.049 ;
     RECT  29.4 2.151 29.712 41.049 ;
     RECT  34.8 2.151 35.112 41.049 ;
     RECT  40.2 2.151 40.512 41.049 ;
     RECT  2.4 41.049 2.52 41.063 ;
     RECT  7.8 41.049 7.92 41.063 ;
     RECT  13.2 41.049 13.32 41.063 ;
     RECT  18.6 41.049 18.72 41.063 ;
     RECT  24 41.049 24.12 41.063 ;
     RECT  29.4 41.049 29.52 41.063 ;
     RECT  34.8 41.049 34.92 41.063 ;
     RECT  40.2 41.049 40.32 41.063 ;
     RECT  12.024 22.741 13.2 23.027 ;
  END
END ot_qkh_head_score_native
END LIBRARY
